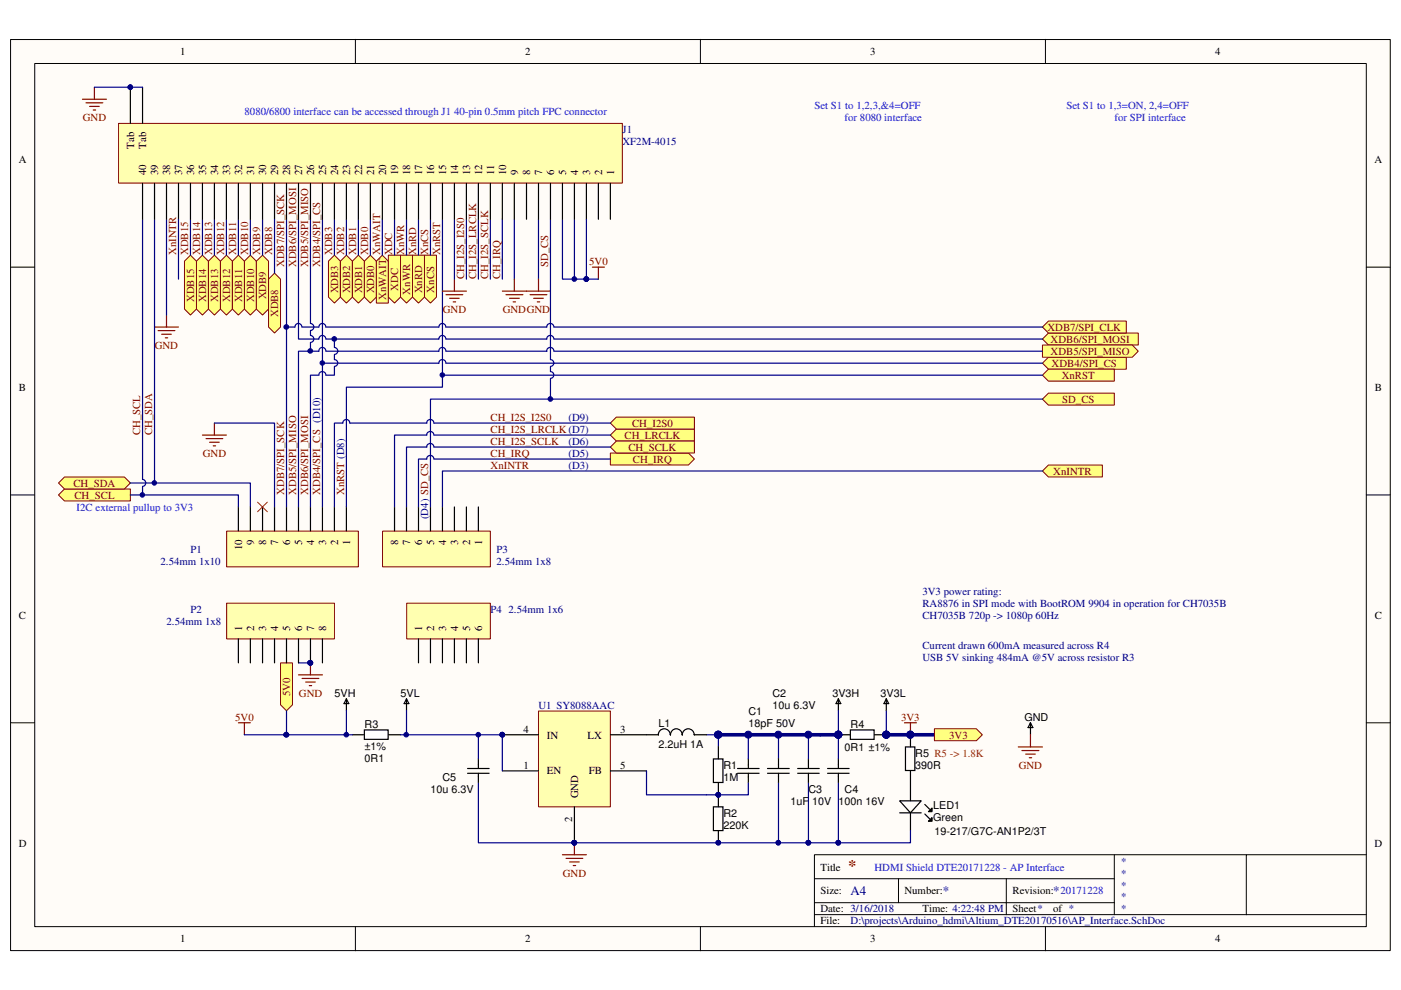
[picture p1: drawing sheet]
<svg xmlns="http://www.w3.org/2000/svg" width="297mm" height="210mm" viewBox="0 0 297 210" stroke-linecap="round" stroke-linejoin="round" font-family="sans-serif">
<defs><g id="words">
<text font-size="3.4" fill="#800000" x="179.8" y="184.6">*</text>
<g font-size="2.8" fill="#000080">
<text x="180.3" y="189.8">A4</text>
<text x="199.9" y="189.8">*</text>
<text x="223.3" y="189.8">*</text>
</g>
<g font-size="2.3">
<text x="38.2" y="11.7">1</text>
<text x="111.4" y="11.7">2</text>
<text x="184.5" y="11.7">3</text>
<text x="257.6" y="11.7">4</text>
<text x="4" y="34.5">A</text>
<text x="28.4" y="31.5" transform="rotate(-90 28.4 31.5)">Tab</text>
<text x="31" y="31.5" transform="rotate(-90 31 31.5)">Tab</text>
<text x="291.4" y="34.5">A</text>
<text x="31" y="37.1" transform="rotate(-90 31 37.1)">40</text>
<text x="33.5" y="37.1" transform="rotate(-90 33.5 37.1)">39</text>
<text x="36.1" y="37.1" transform="rotate(-90 36.1 37.1)">38</text>
<text x="38.6" y="37.1" transform="rotate(-90 38.6 37.1)">37</text>
<text x="41.2" y="37.1" transform="rotate(-90 41.2 37.1)">36</text>
<text x="43.7" y="37.1" transform="rotate(-90 43.7 37.1)">35</text>
<text x="46.3" y="37.1" transform="rotate(-90 46.3 37.1)">34</text>
<text x="48.8" y="37.1" transform="rotate(-90 48.8 37.1)">33</text>
<text x="51.3" y="37.1" transform="rotate(-90 51.3 37.1)">32</text>
<text x="53.9" y="37.1" transform="rotate(-90 53.9 37.1)">31</text>
<text x="56.4" y="37.1" transform="rotate(-90 56.4 37.1)">30</text>
<text x="59" y="37.1" transform="rotate(-90 59 37.1)">29</text>
<text x="61.5" y="37.1" transform="rotate(-90 61.5 37.1)">28</text>
<text x="64.1" y="37.1" transform="rotate(-90 64.1 37.1)">27</text>
<text x="66.6" y="37.1" transform="rotate(-90 66.6 37.1)">26</text>
<text x="69.2" y="37.1" transform="rotate(-90 69.2 37.1)">25</text>
<text x="71.7" y="37.1" transform="rotate(-90 71.7 37.1)">24</text>
<text x="74.2" y="37.1" transform="rotate(-90 74.2 37.1)">23</text>
<text x="76.8" y="37.1" transform="rotate(-90 76.8 37.1)">22</text>
<text x="79.3" y="37.1" transform="rotate(-90 79.3 37.1)">21</text>
<text x="81.9" y="37.1" transform="rotate(-90 81.9 37.1)">20</text>
<text x="84.4" y="37.1" transform="rotate(-90 84.4 37.1)">19</text>
<text x="86.9" y="37.1" transform="rotate(-90 86.9 37.1)">18</text>
<text x="89.5" y="37.1" transform="rotate(-90 89.5 37.1)">17</text>
<text x="92.1" y="37.1" transform="rotate(-90 92.1 37.1)">16</text>
<text x="94.6" y="37.1" transform="rotate(-90 94.6 37.1)">15</text>
<text x="97.2" y="37.1" transform="rotate(-90 97.2 37.1)">14</text>
<text x="99.7" y="37.1" transform="rotate(-90 99.7 37.1)">13</text>
<text x="102.2" y="37.1" transform="rotate(-90 102.2 37.1)">12</text>
<text x="104.8" y="37.1" transform="rotate(-90 104.8 37.1)">11</text>
<text x="107.3" y="37.1" transform="rotate(-90 107.3 37.1)">10</text>
<text x="109.9" y="37.1" transform="rotate(-90 109.9 37.1)">9</text>
<text x="112.4" y="37.1" transform="rotate(-90 112.4 37.1)">8</text>
<text x="114.9" y="37.1" transform="rotate(-90 114.9 37.1)">7</text>
<text x="117.5" y="37.1" transform="rotate(-90 117.5 37.1)">6</text>
<text x="120.1" y="37.1" transform="rotate(-90 120.1 37.1)">5</text>
<text x="122.6" y="37.1" transform="rotate(-90 122.6 37.1)">4</text>
<text x="125.1" y="37.1" transform="rotate(-90 125.1 37.1)">3</text>
<text x="127.7" y="37.1" transform="rotate(-90 127.7 37.1)">2</text>
<text x="130.2" y="37.1" transform="rotate(-90 130.2 37.1)">1</text>
<text x="4" y="82.8">B</text>
<text x="291.5" y="82.8">B</text>
<text x="51.3" y="116.7" transform="rotate(-90 51.3 116.7)">10</text>
<text x="53.9" y="115.5" transform="rotate(-90 53.9 115.5)">9</text>
<text x="56.4" y="115.5" transform="rotate(-90 56.4 115.5)">8</text>
<text x="59" y="115.5" transform="rotate(-90 59 115.5)">7</text>
<text x="61.5" y="115.5" transform="rotate(-90 61.5 115.5)">6</text>
<text x="64.1" y="115.5" transform="rotate(-90 64.1 115.5)">5</text>
<text x="66.6" y="115.5" transform="rotate(-90 66.6 115.5)">4</text>
<text x="69.2" y="115.5" transform="rotate(-90 69.2 115.5)">3</text>
<text x="71.7" y="115.5" transform="rotate(-90 71.7 115.5)">2</text>
<text x="74.2" y="115.5" transform="rotate(-90 74.2 115.5)">1</text>
<text x="84.4" y="115.5" transform="rotate(-90 84.4 115.5)">8</text>
<text x="86.9" y="115.5" transform="rotate(-90 86.9 115.5)">7</text>
<text x="89.5" y="115.5" transform="rotate(-90 89.5 115.5)">6</text>
<text x="92.1" y="115.5" transform="rotate(-90 92.1 115.5)">5</text>
<text x="94.6" y="115.5" transform="rotate(-90 94.6 115.5)">4</text>
<text x="97.2" y="115.5" transform="rotate(-90 97.2 115.5)">3</text>
<text x="99.7" y="115.5" transform="rotate(-90 99.7 115.5)">2</text>
<text x="102.2" y="115.5" transform="rotate(-90 102.2 115.5)">1</text>
<text x="4" y="131.2">C</text>
<text x="291.5" y="131.2">C</text>
<text x="51.3" y="133.7" transform="rotate(-90 51.3 133.7)">1</text>
<text x="53.9" y="133.7" transform="rotate(-90 53.9 133.7)">2</text>
<text x="56.4" y="133.7" transform="rotate(-90 56.4 133.7)">3</text>
<text x="59" y="133.7" transform="rotate(-90 59 133.7)">4</text>
<text x="61.5" y="133.7" transform="rotate(-90 61.5 133.7)">5</text>
<text x="64.1" y="133.7" transform="rotate(-90 64.1 133.7)">6</text>
<text x="66.6" y="133.7" transform="rotate(-90 66.6 133.7)">7</text>
<text x="69.2" y="133.7" transform="rotate(-90 69.2 133.7)">8</text>
<text x="89.5" y="133.7" transform="rotate(-90 89.5 133.7)">1</text>
<text x="92.1" y="133.7" transform="rotate(-90 92.1 133.7)">2</text>
<text x="94.6" y="133.7" transform="rotate(-90 94.6 133.7)">3</text>
<text x="97.2" y="133.7" transform="rotate(-90 97.2 133.7)">4</text>
<text x="99.7" y="133.7" transform="rotate(-90 99.7 133.7)">5</text>
<text x="102.2" y="133.7" transform="rotate(-90 102.2 133.7)">6</text>
<text x="70.9" y="147.7">5VH</text>
<text x="84.9" y="147.7">5VL</text>
<text x="163.8" y="147.7">C2</text>
<text x="176.5" y="147.7">3V3H</text>
<text x="186.7" y="147.7">3V3L</text>
<text x="77.3" y="154.3">R3</text>
<text x="111" y="155.3">4</text>
<text x="131.5" y="155.3">3</text>
<text x="139.6" y="154.1">L1</text>
<text x="158.7" y="154.1">18pF 50V</text>
<text x="158.7" y="151.5">C1</text>
<text x="163.8" y="150.2">10u 6.3V</text>
<text x="180.3" y="154.3">R4</text>
<text x="217.2" y="152.8">GND</text>
<text x="77.3" y="158.9">±1%</text>
<text x="77.3" y="161.5">0R1</text>
<text x="115.9" y="156.6">IN</text>
<text x="124.6" y="156.6">LX</text>
<text x="139.6" y="158.7">2.2uH 1A</text>
<text x="179.1" y="159.2">0R1 ±1%</text>
<text x="194.1" y="160.4">R5 R5 -&gt; 1.8K</text>
<text x="93.8" y="165.5">C5</text>
<text x="111" y="162.9">1</text>
<text x="115.9" y="164.2">EN</text>
<text x="124.8" y="164.2">FB</text>
<text x="131.5" y="162.9">5</text>
<text x="153.4" y="165.5">1M</text>
<text x="153.4" y="163">R1</text>
<text x="194.1" y="163">390R</text>
<text x="91.3" y="168.1">10u 6.3V</text>
<text x="122.6" y="169.3" transform="rotate(-90 122.6 169.3)">GND</text>
<text x="153.4" y="173.1">R2</text>
<text x="167.6" y="170.6">1uF 10V</text>
<text x="171.4" y="168.1">C3</text>
<text x="177.8" y="170.6">100n 16V</text>
<text x="179.1" y="168.1">C4</text>
<text x="197.9" y="171.6">LED1</text>
<text x="4" y="179.5">D</text>
<text x="121.3" y="174.2" transform="rotate(-90 121.3 174.2)">2</text>
<text x="153.4" y="175.7">220K</text>
<text x="197.9" y="174.2">Green</text>
<text x="198.1" y="177">19-217/G7C-AN1P2/3T</text>
<text x="291.4" y="179.5">D</text>
<text x="173.9" y="184.6">Title</text>
<text x="173.9" y="189.7">Size:</text>
<text x="191.8" y="189.7">Number:</text>
<text x="214.7" y="189.7">Revision: 20171228</text>
<text x="173.9" y="193.5">Date: 3/16/2018</text>
<text x="173.9" y="196">File:</text>
<text x="195.6" y="193.5">Time: 4:22:48 PM</text>
<text x="214.7" y="193.5">Sheet*</text>
<text x="223.3" y="193.5">of *</text>
<text x="38.2" y="199.8">1</text>
<text x="111.4" y="199.8">2</text>
<text x="184.5" y="199.8">3</text>
<text x="257.6" y="199.8">4</text>
</g>
<g font-size="2.3" fill="#00f">
<text x="172.7" y="23.1">Set S1 to 1,2,3,&amp;4=OFF</text>
<text x="226.1" y="23.1">Set S1 to 1,3=ON, 2,4=OFF</text>
<text x="51.9" y="24.4">8080/6800 interface can be accessed through J1 40-pin 0.5mm pitch FPC connector</text>
<text x="179.1" y="25.7">for 8080 interface</text>
<text x="236.3" y="25.7">for SPI interface</text>
<text x="16.3" y="108.3">I2C external pullup to 3V3</text>
<text x="185.4" y="184.6">HDMI Shield DTE20171228 - AP Interface</text>
</g>
<g font-size="2.3" fill="#800000">
<text x="17.6" y="25.7">GND</text>
<text x="37.4" y="54.1" transform="rotate(-90 37.4 54.1)">XnINTR</text>
<text x="39.9" y="54.1" transform="rotate(-90 39.9 54.1)">XDB15</text>
<text x="42.5" y="54.1" transform="rotate(-90 42.5 54.1)">XDB14</text>
<text x="45" y="54.1" transform="rotate(-90 45 54.1)">XDB13</text>
<text x="47.5" y="54.1" transform="rotate(-90 47.5 54.1)">XDB12</text>
<text x="50.1" y="54.1" transform="rotate(-90 50.1 54.1)">XDB11</text>
<text x="52.6" y="54.1" transform="rotate(-90 52.6 54.1)">XDB10</text>
<text x="55.2" y="54.1" transform="rotate(-90 55.2 54.1)">XDB9</text>
<text x="57.7" y="54.1" transform="rotate(-90 57.7 54.1)">XDB8</text>
<text x="60.2" y="56.7" transform="rotate(-90 60.2 56.7)">XDB7/SPI_SCK</text>
<text x="62.8" y="56.7" transform="rotate(-90 62.8 56.7)">XDB6/SPI_MOSI</text>
<text x="65.4" y="56.7" transform="rotate(-90 65.4 56.7)">XDB5/SPI_MISO</text>
<text x="67.9" y="56.7" transform="rotate(-90 67.9 56.7)">XDB4/SPI_CS</text>
<text x="70.4" y="54.1" transform="rotate(-90 70.4 54.1)">XDB3</text>
<text x="73" y="54.1" transform="rotate(-90 73 54.1)">XDB2</text>
<text x="75.5" y="54.1" transform="rotate(-90 75.5 54.1)">XDB1</text>
<text x="78.1" y="54.1" transform="rotate(-90 78.1 54.1)">XDB0</text>
<text x="80.6" y="54.1" transform="rotate(-90 80.6 54.1)">XnWAIT</text>
<text x="83.1" y="54.1" transform="rotate(-90 83.1 54.1)">XDC</text>
<text x="85.7" y="54.1" transform="rotate(-90 85.7 54.1)">XnWR</text>
<text x="88.2" y="54.1" transform="rotate(-90 88.2 54.1)">XnRD</text>
<text x="90.8" y="54.1" transform="rotate(-90 90.8 54.1)">XnCS</text>
<text x="93.3" y="54.1" transform="rotate(-90 93.3 54.1)">XnRST</text>
<text x="98.4" y="59.2" transform="rotate(-90 98.4 59.2)">CH_I2S_I2S0</text>
<text x="101" y="59.2" transform="rotate(-90 101 59.2)">CH_I2S_LRCLK</text>
<text x="103.5" y="59.2" transform="rotate(-90 103.5 59.2)">CH_I2S_SCLK</text>
<text x="106" y="59.2" transform="rotate(-90 106 59.2)">CH_IRQ</text>
<text x="116.2" y="56.7" transform="rotate(-90 116.2 56.7)">SD_CS</text>
<text x="124.9" y="56.2">5V0</text>
<text x="41.2" y="64.1" transform="rotate(-90 41.2 64.1)">XDB15</text>
<text x="43.7" y="64.1" transform="rotate(-90 43.7 64.1)">XDB14</text>
<text x="46.3" y="64.1" transform="rotate(-90 46.3 64.1)">XDB13</text>
<text x="48.8" y="64.1" transform="rotate(-90 48.8 64.1)">XDB12</text>
<text x="51.3" y="64.1" transform="rotate(-90 51.3 64.1)">XDB11</text>
<text x="53.9" y="64.1" transform="rotate(-90 53.9 64.1)">XDB10</text>
<text x="56.4" y="63.5" transform="rotate(-90 56.4 63.5)">XDB9</text>
<text x="71.7" y="62.2" transform="rotate(-90 71.7 62.2)">XDB3</text>
<text x="74.2" y="62.2" transform="rotate(-90 74.2 62.2)">XDB2</text>
<text x="76.8" y="62.2" transform="rotate(-90 76.8 62.2)">XDB1</text>
<text x="79.3" y="62.2" transform="rotate(-90 79.3 62.2)">XDB0</text>
<text x="81.9" y="63.6" transform="rotate(-90 81.9 63.6)">XnWAIT</text>
<text x="84.4" y="61.6" transform="rotate(-90 84.4 61.6)">XDC</text>
<text x="86.9" y="62.4" transform="rotate(-90 86.9 62.4)">XnWR</text>
<text x="89.5" y="62.2" transform="rotate(-90 89.5 62.2)">XnRD</text>
<text x="92.1" y="62" transform="rotate(-90 92.1 62)">XnCS</text>
<text x="59" y="67.3" transform="rotate(-90 59 67.3)">XDB8</text>
<text x="93.9" y="66.3">GND</text>
<text x="106.6" y="66.3">GNDGND</text>
<text x="222.1" y="70.1">XDB7/SPI_CLK</text>
<text x="32.8" y="74">GND</text>
<text x="222.8" y="72.7">XDB6/SPI_MOSI</text>
<text x="222.8" y="75.2">XDB5/SPI_MISO</text>
<text x="223" y="77.8">XDB4/SPI_CS</text>
<text x="225.1" y="80.3">XnRST</text>
<text x="104" y="89.2">CH_I2S_I2S0</text>
<text x="225.2" y="85.4">SD_CS</text>
<text x="29.7" y="92.2" transform="rotate(-90 29.7 92.2)">CH_SCL</text>
<text x="32.3" y="92.2" transform="rotate(-90 32.3 92.2)">CH_SDA</text>
<text x="104" y="94.3">CH_I2S_SCLK</text>
<text x="104" y="91.8">CH_I2S_LRCLK(D7)</text>
<text x="132.4" y="93">CH_LRCLK</text>
<text x="133.2" y="95.6">CH_SCLK</text>
<text x="134" y="90.5">CH_I2S0</text>
<text x="43" y="96.9">GND</text>
<text x="104" y="96.9">CH_IRQ</text>
<text x="104" y="99.4">XnINTR</text>
<text x="134.2" y="98.1">CH_IRQ</text>
<text x="223.3" y="100.7">XnINTR</text>
<text x="15.6" y="103.2">CH_SDA</text>
<text x="15.8" y="105.7">CH_SCL</text>
<text x="60.2" y="105" transform="rotate(-90 60.2 105)">XDB7/SPI_SCK</text>
<text x="62.8" y="105" transform="rotate(-90 62.8 105)">XDB5/SPI_MISO</text>
<text x="65.4" y="105" transform="rotate(-90 65.4 105)">XDB6/SPI_MOSI</text>
<text x="67.9" y="105" transform="rotate(-90 67.9 105)">XDB4/SPI_CS (D10)</text>
<text x="73" y="105" transform="rotate(-90 73 105)">XnRST (D8)</text>
<text x="61.5" y="147.6" transform="rotate(-90 61.5 147.6)">5V0</text>
<text x="63.4" y="147.7">GND</text>
<text x="49.9" y="152.8">5V0</text>
<text x="191" y="152.8">3V3</text>
<text x="201.2" y="156.6">3V3</text>
<text x="216" y="162.9">GND</text>
<text x="119.3" y="185.8">GND</text>
</g>
<g font-size="2.3" fill="#000080">
<text x="132" y="28.2">J1</text>
<text x="132" y="30.7">XF2M-4015</text>
<text x="120.5" y="89.2">(D9)</text>
<text x="120.5" y="94.3">(D6)</text>
<text x="120.5" y="96.9">(D5)</text>
<text x="120.5" y="99.4">(D3)</text>
<text x="90.8" y="110.1" transform="rotate(-90 90.8 110.1)">(D4) SD_CS</text>
<text x="34" y="119.7">2.54mm 1x10</text>
<text x="40.4" y="117.2">P1</text>
<text x="105.3" y="117.2">P3</text>
<text x="105.3" y="119.7">2.54mm 1x8</text>
<text x="40.4" y="129.9">P2</text>
<text x="104" y="129.9">P4 2.54mm 1x6</text>
<text x="195.6" y="126.1">3V3 power rating:</text>
<text x="195.6" y="128.7">RA8876 in SPI mode with BootROM 9904 in operation for CH7035B</text>
<text x="195.6" y="131.2">CH7035B 720p -&gt; 1080p 60Hz</text>
<text x="35.3" y="132.5">2.54mm 1x8</text>
<text x="195.6" y="137.5">Current drawn 600mA measured across R4</text>
<text x="195.6" y="140.1">USB 5V sinking 484mA @5V across resistor R3</text>
<text x="114.2" y="150.2">U1 SY8088AAC</text>
<text x="237.6" y="183.3">*</text>
<text x="237.6" y="185.8">*</text>
<text x="237.6" y="188.4">*</text>
<text x="237.6" y="190.9">*</text>
<text x="180.3" y="196">D:\projects\Arduino_hdmi\Altium_DTE20170516\AP_Interface.SchDoc</text>
<text x="237.6" y="193.5">*</text>
</g>
</g></defs>
<path d="M2.3 8.4h292.5v193.1h-292.5z" fill="#fffcf8"/>
<path d="M2.2 8.4h292.6v193.1h-292.6z" fill="none" stroke="#000" stroke-width=".21"/>
<path d="M7.4 13.5h282.3v183h-282.3z" fill="#fffcf8"/>
<g fill="none" stroke="#000" stroke-width=".21">
<path d="M7.4 13.5h282.3v183h-282.3zM75.3 8.3v5.1M148.5 8.3v5.1M221.7 8.3v5.1M2.2 56.6h5.1M289.7 56.6h5.1M2.2 104.9h5.1M289.7 104.9h5.1M2.2 153.2h5.1M289.7 153.2h5.1M75.3 196.5v5.1M148.5 196.5v5.1"/>
<path d="M172.7 186.3h63.6M172.7 193.9h117M172.7 191.4h63.6M190.5 186.3v5.1M213.4 186.3v7.6M221.7 196.5v5.1M236.3 181.2v12.7M264.2 181.2h-91.5v15.3M289.7 181.2h-25.5v12.7"/>
</g>
<path d="M63.3 143.1h5.1M64 143.8h3.6M64.8 144.6h2M65.6 145.4h.5M65.8 140.5v2.6" fill="none" stroke="#800000" stroke-width=".25"/>
<circle cx="65.8" cy="140.5" r=".49" fill="#000080"/>
<circle cx="65.8" cy="140.5" r=".49" fill="none" stroke="#000080" stroke-width=".21"/>
<path d="M42.9 92.2h5.1M43.7 93h3.5M44.4 93.8h2.1M45.2 94.5h.5M45.5 89.7v2.5M50.5 153.2h2.6M51.8 153.2v2.6" fill="none" stroke="#800000" stroke-width=".25"/>
<path d="M59.5 140.5h2.5v8.9l-1.3 1.3-1.2-1.3z" fill-rule="evenodd" fill="#ffff80"/>
<path d="M59.5 140.5h2.5v8.9l-1.3 1.3-1.2-1.3z" fill="none" stroke="#800000" stroke-width=".21"/>
<path d="M12.4 104.9l1.3-1.2h13.9v2.5h-13.9z" fill-rule="evenodd" fill="#ffff80"/>
<path d="M12.4 104.9l1.3-1.2h13.9v2.5h-13.9z" fill="none" stroke="#800000" stroke-width=".21"/>
<path d="M12.4 102.4l1.3-1.3h12.7l1.2 1.3-1.2 1.3h-12.7z" fill-rule="evenodd" fill="#ffff80"/>
<path d="M12.4 102.4l1.3-1.3h12.7l1.2 1.3-1.2 1.3h-12.7z" fill="none" stroke="#800000" stroke-width=".21"/>
<path d="M221 77l1.3-1.3h16.5v2.6h-16.5z" fill-rule="evenodd" fill="#ffff80"/>
<path d="M221 77l1.3-1.3h16.5v2.6h-16.5z" fill="none" stroke="#800000" stroke-width=".21"/>
<path d="M221 71.9l1.3-1.3h19v2.6h-19z" fill-rule="evenodd" fill="#ffff80"/>
<path d="M221 71.9l1.3-1.3h19v2.6h-19z" fill="none" stroke="#800000" stroke-width=".21"/>
<path d="M221 69.3l1.3-1.2h16.5v2.5h-16.5z" fill-rule="evenodd" fill="#ffff80"/>
<path d="M221 69.3l1.3-1.2h16.5v2.5h-16.5z" fill="none" stroke="#800000" stroke-width=".21"/>
<path d="M221 79.5l1.3-1.2h14v2.5h-14z" fill-rule="evenodd" fill="#ffff80"/>
<path d="M221 79.5l1.3-1.2h14v2.5h-14z" fill="none" stroke="#800000" stroke-width=".21"/>
<path d="M129.4 96.1h16.6l1.2 1.2-1.2 1.3h-16.6z" fill-rule="evenodd" fill="#ffff80"/>
<path d="M129.4 96.1h16.6l1.2 1.2-1.2 1.3h-16.6z" fill="none" stroke="#800000" stroke-width=".21"/>
<path d="M221 73.2h19.1l1.2 1.3-1.2 1.2h-19.1z" fill-rule="evenodd" fill="#ffff80"/>
<path d="M221 73.2h19.1l1.2 1.3-1.2 1.2h-19.1z" fill="none" stroke="#800000" stroke-width=".21"/>
<path d="M221 84.6l1.3-1.2h14v2.5h-14z" fill-rule="evenodd" fill="#ffff80"/>
<path d="M221 84.6l1.3-1.2h14v2.5h-14z" fill="none" stroke="#800000" stroke-width=".21"/>
<path d="M42.9 54.1l1.3 1.3v10.1l-1.3 1.3-1.2-1.3v-10.1z" fill-rule="evenodd" fill="#ffff80"/>
<path d="M42.9 54.1l1.3 1.3v10.1l-1.3 1.3-1.2-1.3v-10.1z" fill="none" stroke="#800000" stroke-width=".21"/>
<path d="M46.7 55.4l1.3-1.3 1.3 1.3v10.1l-1.3 1.3-1.3-1.3z" fill-rule="evenodd" fill="#ffff80"/>
<path d="M46.7 55.4l1.3-1.3 1.3 1.3v10.1l-1.3 1.3-1.3-1.3z" fill="none" stroke="#800000" stroke-width=".21"/>
<path d="M51.8 55.4l1.3-1.3 1.3 1.3v10.1l-1.3 1.3-1.3-1.3z" fill-rule="evenodd" fill="#ffff80"/>
<path d="M51.8 55.4l1.3-1.3 1.3 1.3v10.1l-1.3 1.3-1.3-1.3z" fill="none" stroke="#800000" stroke-width=".21"/>
<path d="M56.9 59.2l1.3-1.3 1.3 1.3v10.1l-1.3 1.3-1.3-1.3z" fill-rule="evenodd" fill="#ffff80"/>
<path d="M56.9 59.2l1.3-1.3 1.3 1.3v10.1l-1.3 1.3-1.3-1.3z" fill="none" stroke="#800000" stroke-width=".21"/>
<path d="M221 99.9l1.3-1.3h11.4v2.5h-11.4z" fill-rule="evenodd" fill="#ffff80"/>
<path d="M221 99.9l1.3-1.3h11.4v2.5h-11.4z" fill="none" stroke="#800000" stroke-width=".21"/>
<path d="M39.1 55.4l1.3-1.3 1.3 1.3v10.1l-1.3 1.3-1.3-1.3z" fill-rule="evenodd" fill="#ffff80"/>
<path d="M39.1 55.4l1.3-1.3 1.3 1.3v10.1l-1.3 1.3-1.3-1.3z" fill="none" stroke="#800000" stroke-width=".21"/>
<path d="M44.2 55.4l1.3-1.3 1.2 1.3v10.1l-1.2 1.3-1.3-1.3z" fill-rule="evenodd" fill="#ffff80"/>
<path d="M44.2 55.4l1.3-1.3 1.2 1.3v10.1l-1.2 1.3-1.3-1.3z" fill="none" stroke="#800000" stroke-width=".21"/>
<path d="M49.3 55.4l1.2-1.3 1.3 1.3v10.1l-1.3 1.3-1.2-1.3z" fill-rule="evenodd" fill="#ffff80"/>
<path d="M49.3 55.4l1.2-1.3 1.3 1.3v10.1l-1.3 1.3-1.2-1.3z" fill="none" stroke="#800000" stroke-width=".21"/>
<path d="M54.4 55.4l1.3-1.3 1.2 1.3v10.1l-1.2 1.3-1.3-1.3z" fill-rule="evenodd" fill="#ffff80"/>
<path d="M54.4 55.4l1.3-1.3 1.2 1.3v10.1l-1.2 1.3-1.3-1.3z" fill="none" stroke="#800000" stroke-width=".21"/>
<path d="M69.6 55.4l1.3-1.3 1.3 1.3v7.6l-1.3 1.3-1.3-1.3z" fill-rule="evenodd" fill="#ffff80"/>
<path d="M69.6 55.4l1.3-1.3 1.3 1.3v7.6l-1.3 1.3-1.3-1.3z" fill="none" stroke="#800000" stroke-width=".21"/>
<path d="M72.2 55.4l1.2-1.3 1.3 1.3v7.6l-1.3 1.3-1.2-1.3z" fill-rule="evenodd" fill="#ffff80"/>
<path d="M72.2 55.4l1.2-1.3 1.3 1.3v7.6l-1.3 1.3-1.2-1.3z" fill="none" stroke="#800000" stroke-width=".21"/>
<path d="M74.7 55.4l1.3-1.3 1.3 1.3v7.6l-1.3 1.3-1.3-1.3z" fill-rule="evenodd" fill="#ffff80"/>
<path d="M74.7 55.4l1.3-1.3 1.3 1.3v7.6l-1.3 1.3-1.3-1.3z" fill="none" stroke="#800000" stroke-width=".21"/>
<path d="M77.3 55.4l1.2-1.3 1.3 1.3v7.6l-1.3 1.3-1.2-1.3z" fill-rule="evenodd" fill="#ffff80"/>
<path d="M77.3 55.4l1.2-1.3 1.3 1.3v7.6l-1.3 1.3-1.2-1.3z" fill="none" stroke="#800000" stroke-width=".21"/>
<path d="M79.8 55.4l1.3-1.3 1.2 1.3v8.9h-2.5z" fill-rule="evenodd" fill="#ffff80"/>
<path d="M79.8 55.4l1.3-1.3 1.2 1.3v8.9h-2.5z" fill="none" stroke="#800000" stroke-width=".21"/>
<path d="M82.3 54.1h2.6v8.9l-1.3 1.3-1.3-1.3z" fill-rule="evenodd" fill="#ffff80"/>
<path d="M82.3 54.1h2.6v8.9l-1.3 1.3-1.3-1.3z" fill="none" stroke="#800000" stroke-width=".21"/>
<path d="M84.9 54.1h2.6v8.9l-1.3 1.3-1.3-1.3z" fill-rule="evenodd" fill="#ffff80"/>
<path d="M84.9 54.1h2.6v8.9l-1.3 1.3-1.3-1.3z" fill="none" stroke="#800000" stroke-width=".21"/>
<path d="M90 54.1h2.5v8.9l-1.2 1.3-1.3-1.3z" fill-rule="evenodd" fill="#ffff80"/>
<path d="M90 54.1h2.5v8.9l-1.2 1.3-1.3-1.3z" fill="none" stroke="#800000" stroke-width=".21"/>
<path d="M87.5 54.1h2.5v8.9l-1.3 1.3-1.2-1.3z" fill-rule="evenodd" fill="#ffff80"/>
<path d="M87.5 54.1h2.5v8.9l-1.3 1.3-1.2-1.3z" fill="none" stroke="#800000" stroke-width=".21"/>
<path d="M125.6 56.6h2.5M126.9 56.6v2.6" fill="none" stroke="#800000" stroke-width=".25"/>
<path d="M63.3 140.5h2.5" fill="none" stroke="#000080" stroke-width=".25"/>
<circle cx="65.8" cy="140.5" r=".49" fill="#000080"/>
<circle cx="65.8" cy="140.5" r=".49" fill="none" stroke="#000080" stroke-width=".21"/>
<path d="M129.4 92.2l1.3-1.2h16.5v2.5h-16.5z" fill-rule="evenodd" fill="#ffff80"/>
<path d="M129.4 92.2l1.3-1.2h16.5v2.5h-16.5z" fill="none" stroke="#800000" stroke-width=".21"/>
<path d="M129.4 94.8l1.3-1.3h16.5v2.6h-16.5z" fill-rule="evenodd" fill="#ffff80"/>
<path d="M129.4 94.8l1.3-1.3h16.5v2.6h-16.5z" fill="none" stroke="#800000" stroke-width=".21"/>
<path d="M129.4 89.7l1.3-1.3h16.5v2.6h-16.5z" fill-rule="evenodd" fill="#ffff80"/>
<path d="M129.4 89.7l1.3-1.3h16.5v2.6h-16.5z" fill="none" stroke="#800000" stroke-width=".21"/>
<path d="M48.1 112.6h27.9v7.6h-27.9z" fill="#ffffb0"/>
<path d="M48 112.6h28v7.6h-28z" fill="none" stroke="#800000" stroke-width=".21"/>
<path d="M50.5 107.5v5.1M53.1 107.5v5.1M55.7 107.5v5.1M58.2 107.5v5.1M60.7 107.5v5.1M63.3 107.5v5.1M65.8 107.5v5.1M68.4 107.5v5.1M70.9 107.5v5.1M73.4 107.5v5.1" fill="none" stroke="#000" stroke-width=".25"/>
<path d="M81.1 112.6h22.9v7.6h-22.9z" fill="#ffffb0"/>
<path d="M81.1 112.6h22.9v7.6h-22.9z" fill="none" stroke="#800000" stroke-width=".21"/>
<path d="M83.6 107.5v5.1M86.2 107.5v5.1M88.7 107.5v5.1M91.3 107.5v5.1M93.8 107.5v5.1M96.3 107.5v5.1M98.9 107.5v5.1M101.4 107.5v5.1" fill="none" stroke="#000" stroke-width=".25"/>
<path d="M48.1 127.9h22.8v7.6h-22.8z" fill="#ffffb0"/>
<path d="M48 127.9h22.9v7.6h-22.9z" fill="none" stroke="#800000" stroke-width=".21"/>
<path d="M50.5 135.5v5M53.1 135.5v5M55.7 135.5v5M58.2 135.5v5M60.7 135.5v5M63.3 135.5v5M65.8 135.5v5" fill="none" stroke="#000" stroke-width=".25"/>
<circle cx="65.8" cy="140.5" r=".49" fill="#000080"/>
<circle cx="65.8" cy="140.5" r=".49" fill="none" stroke="#000080" stroke-width=".21"/>
<path d="M68.4 135.5v5" fill="none" stroke="#000" stroke-width=".25"/>
<circle cx="65.8" cy="140.5" r=".49" fill="#000080"/>
<circle cx="65.8" cy="140.5" r=".49" fill="none" stroke="#000080" stroke-width=".21"/>
<path d="M86.3 127.9h17.7v7.6h-17.7z" fill="#ffffb0"/>
<path d="M86.2 127.9h17.8v7.6h-17.8z" fill="none" stroke="#800000" stroke-width=".21"/>
<path d="M88.7 135.5v5M91.3 135.5v5M93.8 135.5v5M96.3 135.5v5M98.9 135.5v5M101.4 135.5v5" fill="none" stroke="#000" stroke-width=".25"/>
<g fill="none" stroke="#000080" stroke-width=".25">
<path d="M40.4 46.5v7.6M42.9 46.5v7.6M45.5 46.5v7.6M48 46.5v7.6M50.5 46.5v7.6M53.1 46.5v7.6M55.7 46.5v7.6M60.7 46.5v61M68.4 46.5v61M70.9 46.5v7.6M73.4 46.5v7.6M76 46.5v7.6"/>
<path d="M78.5 46.5v7.6M81.1 46.5v7.6M83.6 46.5v7.6M86.2 46.5v7.6M88.7 46.5v7.6M91.3 46.5v7.6M93.8 46.5v35.6h-20.4v25.4M68.4 77h24.6a.74 .74 0 0 1 .8-.8 .74 .74 0 0 1 .7 .8M94.6 77h126.4M45.5 89.7h12.7v17.8"/>
</g>
<path d="M54.6 106.5l2.1 2M56.7 106.5l-2.1 2" fill="none" stroke="#f00" stroke-width=".21"/>
<circle cx="68.4" cy="77" r=".48" fill="#000080"/>
<circle cx="68.4" cy="77" r=".48" fill="none" stroke="#000080" stroke-width=".21"/>
<path d="M93.8 79.5h127.2" fill="none" stroke="#000080" stroke-width=".25"/>
<circle cx="93.8" cy="79.5" r=".48" fill="#000080"/>
<circle cx="93.8" cy="79.5" r=".48" fill="none" stroke="#000080" stroke-width=".21"/>
<path d="M32.8 69.3h5M33.5 70.1h3.6M34.3 70.9h2M35 71.6h.6M35.3 66.8v2.5" fill="none" stroke="#800000" stroke-width=".25"/>
<path d="M32.8 46.5v55.9M35.3 46.5v20.3M27.6 104.9h22.9v2.6M27.6 102.4h25.5v5.1" fill="none" stroke="#000080" stroke-width=".25"/>
<circle cx="32.7" cy="102.4" r=".48" fill="#000080"/>
<circle cx="32.7" cy="102.4" r=".48" fill="none" stroke="#000080" stroke-width=".21"/>
<path d="M30.2 46.5v55.1a.74 .74 0 0 1 .7 .8 .74 .74 0 0 1-.7 .7v1.8" fill="none" stroke="#000080" stroke-width=".25"/>
<circle cx="30.2" cy="104.9" r=".48" fill="#000080"/>
<circle cx="30.2" cy="104.9" r=".48" fill="none" stroke="#000080" stroke-width=".21"/>
<path d="M104 46.5v12.7M106.5 46.5v12.7M109 46.5v12.7" fill="none" stroke="#000080" stroke-width=".25"/>
<path d="M114.2 150.8h15.2v20.3h-15.2z" fill="#ffffb0"/>
<path d="M114.2 150.7h15.2v20.4h-15.2z" fill="none" stroke="#800000" stroke-width=".21"/>
<path d="M129.4 155.8h7.7M121.8 171.1v7.6" fill="none" stroke="#000" stroke-width=".25"/>
<circle cx="121.8" cy="178.7" r=".49" fill="#000080"/>
<circle cx="121.8" cy="178.7" r=".49" fill="none" stroke="#000080" stroke-width=".21"/>
<path d="M106.5 155.8h7.7" fill="none" stroke="#000" stroke-width=".25"/>
<circle cx="106.5" cy="155.8" r=".48" fill="#000080"/>
<circle cx="106.5" cy="155.8" r=".48" fill="none" stroke="#000080" stroke-width=".21"/>
<path d="M106.5 163.4h7.7M129.4 163.4h7.7" fill="none" stroke="#000" stroke-width=".25"/>
<circle cx="121.8" cy="178.7" r=".49" fill="#000080"/>
<circle cx="121.8" cy="178.7" r=".49" fill="none" stroke="#000080" stroke-width=".21"/>
<circle cx="106.5" cy="155.8" r=".48" fill="#000080"/>
<circle cx="106.5" cy="155.8" r=".48" fill="none" stroke="#000080" stroke-width=".21"/>
<path d="M99.1 164h4.6M99.1 162.9h4.6M101.4 160.9v2M101.4 164v2M169.1 164h4.6M169.1 162.9h4.6M171.4 160.9v2M171.4 164v2M175.5 164h4.5M175.5 162.9h4.5M177.8 160.9v2M177.8 164v2" fill="none" stroke="#000" stroke-width=".25"/>
<path d="M121.8 178.7v2.5M119.2 181.2h5.1M120 182h3.6M120.8 182.8h2M121.5 183.5h.5" fill="none" stroke="#800000" stroke-width=".25"/>
<circle cx="121.8" cy="178.7" r=".49" fill="#000080"/>
<circle cx="121.8" cy="178.7" r=".49" fill="none" stroke="#000080" stroke-width=".21"/>
<path d="M191.8 153.2h2.5M193 153.2v2.6" fill="none" stroke="#800000" stroke-width=".25"/>
<circle cx="193" cy="155.8" r=".73" fill="#000080"/>
<circle cx="193" cy="155.8" r=".73" fill="none" stroke="#000080" stroke-width=".21"/>
<path d="M152.3 176.1v2.6" fill="none" stroke="#000" stroke-width=".25"/>
<circle cx="152.3" cy="178.7" r=".49" fill="#000080"/>
<circle cx="152.3" cy="178.7" r=".49" fill="none" stroke="#000080" stroke-width=".21"/>
<path d="M152.3 168.5v2.6" fill="none" stroke="#000" stroke-width=".25"/>
<circle cx="152.3" cy="168.5" r=".49" fill="#000080"/>
<circle cx="152.3" cy="168.5" r=".49" fill="none" stroke="#000080" stroke-width=".21"/>
<path d="M151.3 171.1h2v5h-2z" fill="none" stroke="#000" stroke-width=".25"/>
<circle cx="152.3" cy="178.7" r=".49" fill="#000080"/>
<circle cx="152.3" cy="178.7" r=".49" fill="none" stroke="#000080" stroke-width=".21"/>
<circle cx="152.3" cy="168.5" r=".49" fill="#000080"/>
<circle cx="152.3" cy="168.5" r=".49" fill="none" stroke="#000080" stroke-width=".21"/>
<path d="M101.4 155.8v5.1" fill="none" stroke="#000080" stroke-width=".25"/>
<circle cx="101.4" cy="155.8" r=".49" fill="#000080"/>
<circle cx="101.4" cy="155.8" r=".49" fill="none" stroke="#000080" stroke-width=".21"/>
<path d="M101.4 166v12.7h20.4M137.1 163.4v5.1h12.7" fill="none" stroke="#000080" stroke-width=".25"/>
<circle cx="121.8" cy="178.7" r=".49" fill="#000080"/>
<circle cx="121.8" cy="178.7" r=".49" fill="none" stroke="#000080" stroke-width=".21"/>
<path d="M156.4 162.9h4.5M156.4 164h4.5M158.7 160.9v2M158.7 164v2" fill="none" stroke="#000" stroke-width=".25"/>
<path d="M158.7 155.8v5.1" fill="none" stroke="#000080" stroke-width=".25"/>
<circle cx="158.6" cy="155.8" r=".74" fill="#000080"/>
<circle cx="158.6" cy="155.8" r=".74" fill="none" stroke="#000080" stroke-width=".21"/>
<path d="M171.4 155.8v5.1" fill="none" stroke="#000080" stroke-width=".25"/>
<circle cx="171.4" cy="155.8" r=".74" fill="#000080"/>
<circle cx="171.4" cy="155.8" r=".74" fill="none" stroke="#000080" stroke-width=".21"/>
<path d="M165.1 155.8v5.1" fill="none" stroke="#000080" stroke-width=".25"/>
<circle cx="165" cy="155.8" r=".73" fill="#000080"/>
<circle cx="165" cy="155.8" r=".73" fill="none" stroke="#000080" stroke-width=".21"/>
<path d="M152.3 155.8h21.6" fill="none" stroke="#000080" stroke-width=".76"/>
<circle cx="152.3" cy="155.8" r=".75" fill="#000080"/>
<circle cx="152.3" cy="155.8" r=".75" fill="none" stroke="#000080" stroke-width=".21"/>
<path d="M177.8 155.8v5.1" fill="none" stroke="#000080" stroke-width=".25"/>
<circle cx="177.7" cy="155.8" r=".74" fill="#000080"/>
<circle cx="177.7" cy="155.8" r=".74" fill="none" stroke="#000080" stroke-width=".21"/>
<path d="M96.3 59.2v2.5M109 59.2v2.5M93.8 61.7h5.1M94.6 62.5h3.5M95.3 63.2h2.1M96.1 64h.5M106.5 61.7h5.1M107.3 62.5h3.6M108 63.2h2.1M108.8 64h.5" fill="none" stroke="#800000" stroke-width=".25"/>
<path d="M96.3 46.5v12.7M114.2 46.5v12.7M121.8 46.5v12.7" fill="none" stroke="#000080" stroke-width=".25"/>
<circle cx="121.8" cy="59.2" r=".49" fill="#000080"/>
<circle cx="121.8" cy="59.2" r=".49" fill="none" stroke="#000080" stroke-width=".21"/>
<path d="M98.9 46.5v12.7M106.5 155.8v7.6" fill="none" stroke="#000080" stroke-width=".25"/>
<path d="M218.5 153.2v2.6M218.5 153.2l.5 1.1h-1z" fill="none" stroke="#000" stroke-width=".25"/>
<circle cx="106.5" cy="155.8" r=".48" fill="#000080"/>
<circle cx="106.5" cy="155.8" r=".48" fill="none" stroke="#000080" stroke-width=".21"/>
<path d="M114.2 59.2v2.5M111.6 61.7h5.1M112.4 62.5h3.5M113.2 63.2h2M113.9 64h.5M215.9 158.4h5.1M216.7 159.1h3.6M217.5 159.9h2M218.5 155.8v2.6M218.2 160.7h.5" fill="none" stroke="#800000" stroke-width=".25"/>
<path d="M101.4 46.5v12.7M116.7 46.5v29.7a.72 .72 0 0 1 .7 .8 .72 .72 0 0 1-.7 .7M116.7 77.8v1a.72 .72 0 0 1 .7 .7 .72 .72 0 0 1-.7 .7M116.7 80.3v4.3M221 84.6h-129.7v22.9" fill="none" stroke="#000080" stroke-width=".25"/>
<circle cx="116.7" cy="84.6" r=".49" fill="#000080"/>
<circle cx="116.7" cy="84.6" r=".49" fill="none" stroke="#000080" stroke-width=".21"/>
<path d="M162.7 164h4.6M162.7 162.9h4.6M165.1 160.9v2M165.1 164v2" fill="none" stroke="#000" stroke-width=".25"/>
<path d="M165.1 166v12.7h6.3" fill="none" stroke="#000080" stroke-width=".25"/>
<circle cx="165" cy="178.7" r=".48" fill="#000080"/>
<circle cx="165" cy="178.7" r=".48" fill="none" stroke="#000080" stroke-width=".21"/>
<circle cx="171.4" cy="178.7" r=".49" fill="#000080"/>
<circle cx="171.4" cy="178.7" r=".49" fill="none" stroke="#000080" stroke-width=".21"/>
<path d="M74.7 155.8h2.6M82.3 155.8h2.6" fill="none" stroke="#000" stroke-width=".25"/>
<path d="M77.3 154.8h5v2h-5z" fill-rule="evenodd" fill="#fff"/>
<path d="M77.3 154.8h5v2h-5zM185.4 155.8h2.5" fill="none" stroke="#000" stroke-width=".25"/>
<circle cx="187.9" cy="155.8" r=".74" fill="#000080"/>
<circle cx="187.9" cy="155.8" r=".74" fill="none" stroke="#000080" stroke-width=".21"/>
<path d="M177.8 155.8h2.5" fill="none" stroke="#000" stroke-width=".25"/>
<circle cx="177.7" cy="155.8" r=".74" fill="#000080"/>
<circle cx="177.7" cy="155.8" r=".74" fill="none" stroke="#000080" stroke-width=".21"/>
<path d="M180.3 154.8h5v2h-5z" fill-rule="evenodd" fill="#fff"/>
<path d="M180.3 154.8h5v2h-5z" fill="none" stroke="#000" stroke-width=".25"/>
<circle cx="187.9" cy="155.8" r=".74" fill="#000080"/>
<circle cx="187.9" cy="155.8" r=".74" fill="none" stroke="#000080" stroke-width=".21"/>
<circle cx="177.7" cy="155.8" r=".74" fill="#000080"/>
<circle cx="177.7" cy="155.8" r=".74" fill="none" stroke="#000080" stroke-width=".21"/>
<path d="M84.9 155.8h21.6" fill="none" stroke="#000080" stroke-width=".25"/>
<circle cx="106.5" cy="155.8" r=".48" fill="#000080"/>
<circle cx="106.5" cy="155.8" r=".48" fill="none" stroke="#000080" stroke-width=".21"/>
<path d="M173.9 155.8h3.9" fill="none" stroke="#000080" stroke-width=".76"/>
<circle cx="177.7" cy="155.8" r=".74" fill="#000080"/>
<circle cx="177.7" cy="155.8" r=".74" fill="none" stroke="#000080" stroke-width=".21"/>
<path d="M73.4 148.2v2.5M73.4 148.2l.6 1h-1.1zM86.2 148.2l.5 1h-1zM86.2 148.2v2.5M177.8 148.2l.5 1h-1.1zM177.8 148.2v2.5M187.9 148.2l.5 1h-1zM187.9 148.2v2.5" fill="none" stroke="#000" stroke-width=".25"/>
<path d="M187.9 155.8h10.2" fill="none" stroke="#000080" stroke-width=".76"/>
<circle cx="187.9" cy="155.8" r=".74" fill="#000080"/>
<circle cx="187.9" cy="155.8" r=".74" fill="none" stroke="#000080" stroke-width=".21"/>
<path d="M63.3 46.5v25.4h4.3a.74 .74 0 0 1 .7-.8 .74 .74 0 0 1 .8 .8M60.7 69.3h1.8a.74 .74 0 0 1 .8-.7 .74 .74 0 0 1 .7 .7h3.6a.74 .74 0 0 1 .7-.7 .74 .74 0 0 1 .8 .7M69.1 74.4a.74 .74 0 0 0-.8-.7 .74 .74 0 0 0-.7 .8h-4.3v33M69.1 71.9h23.9a.74 .74 0 0 1 .8-.8 .74 .74 0 0 1 .7 .8M69.1 69.3h23.9a.74 .74 0 0 1 .8-.7 .74 .74 0 0 1 .7 .7M94.5 74.4a.74 .74 0 0 0-.7-.7 .74 .74 0 0 0-.8 .8h-23.9M94.6 71.9h21.3a.76 .76 0 0 1 .8-.8 .76 .76 0 0 1 .7 .8M94.6 69.3h21.3a.76 .76 0 0 1 .8-.7 .76 .76 0 0 1 .7 .7M117.4 74.4a.76 .76 0 0 0-.8-.7 .76 .76 0 0 0-.7 .8h-21.3M117.5 74.5h103.5M117.5 71.9h103.5M117.5 69.3h103.5" fill="none" stroke="#000080" stroke-width=".25"/>
<circle cx="60.7" cy="69.3" r=".5" fill="#000080"/>
<circle cx="60.7" cy="69.3" r=".5" fill="none" stroke="#000080" stroke-width=".21"/>
<path d="M74.2 89.7a.74 .74 0 0 0-.8-.8 .74 .74 0 0 0-.7 .8h-1.8v17.8M74.2 89.7h16.3a.76 .76 0 0 1 .7-.8 .76 .76 0 0 1 .8 .8M92 92.2a.74 .74 0 0 0-.8-.7 .74 .74 0 0 0-.7 .7h-6.9v15.3M92 94.8a.74 .74 0 0 0-.8-.8 .74 .74 0 0 0-.7 .8h-4.3v12.7M92 97.3a.74 .74 0 0 0-.8-.7 .74 .74 0 0 0-.7 .7h-1.8v10.2M92 89.7h37.4M92 92.2h37.4M92 94.8h37.4M92 97.3h37.4M171.4 166v12.7" fill="none" stroke="#000080" stroke-width=".25"/>
<circle cx="171.4" cy="178.7" r=".49" fill="#000080"/>
<circle cx="171.4" cy="178.7" r=".49" fill="none" stroke="#000080" stroke-width=".21"/>
<path d="M121.8 178.7h43.3M158.7 166v2.5h-8.9" fill="none" stroke="#000080" stroke-width=".25"/>
<circle cx="121.8" cy="178.7" r=".49" fill="#000080"/>
<circle cx="121.8" cy="178.7" r=".49" fill="none" stroke="#000080" stroke-width=".21"/>
<circle cx="165" cy="178.7" r=".48" fill="#000080"/>
<circle cx="165" cy="178.7" r=".48" fill="none" stroke="#000080" stroke-width=".21"/>
<path d="M152.3 155.8v2.6" fill="none" stroke="#000080" stroke-width=".25"/>
<circle cx="152.3" cy="155.8" r=".75" fill="#000080"/>
<circle cx="152.3" cy="155.8" r=".75" fill="none" stroke="#000080" stroke-width=".21"/>
<path d="M149.8 155.8h2.5" fill="none" stroke="#000080" stroke-width=".25"/>
<circle cx="152.3" cy="155.8" r=".75" fill="#000080"/>
<circle cx="152.3" cy="155.8" r=".75" fill="none" stroke="#000080" stroke-width=".21"/>
<path d="M137.1 155.8h2.5M139.6 155.8a1.27 1.27 0 0 1 1.2-1.3 1.27 1.27 0 0 1 1.3 1.3M142.2 155.8a1.25 1.25 0 0 1 1.2-1.3 1.25 1.25 0 0 1 1.2 1.3 1.27 1.27 0 0 1 1.3-1.3 1.27 1.27 0 0 1 1.3 1.3M147.2 155.8h2.6" fill="none" stroke="#000" stroke-width=".25"/>
<path d="M198.1 154.5h8.9l1.3 1.3-1.3 1.3h-8.9z" fill-rule="evenodd" fill="#ffff80"/>
<path d="M198.1 154.5h8.9l1.3 1.3-1.3 1.3h-8.9z" fill="none" stroke="#800000" stroke-width=".21"/>
<path d="M60.7 155.8h14" fill="none" stroke="#000080" stroke-width=".25"/>
<circle cx="60.7" cy="155.8" r=".5" fill="#000080"/>
<circle cx="60.7" cy="155.8" r=".5" fill="none" stroke="#000080" stroke-width=".21"/>
<path d="M60.7 150.7v5.1" fill="none" stroke="#000080" stroke-width=".25"/>
<circle cx="60.7" cy="155.8" r=".5" fill="#000080"/>
<circle cx="60.7" cy="155.8" r=".5" fill="none" stroke="#000080" stroke-width=".21"/>
<path d="M190.8 169.8h4.5l-2.3 2.5zM190.8 172.3h4.5M193 166v3.8M193 172.3v3.8M196.1 172.6l1 1M196.1 170.6l1 1M197.6 173.4v.7h-.8zM197.6 171.3v.8h-.8z" fill="none" stroke="#000" stroke-width=".25"/>
<path d="M197.6 173.4v.7h-.8zM197.6 171.3v.8h-.8z" fill="#000"/>
<path d="M177.8 166v12.7" fill="none" stroke="#000080" stroke-width=".25"/>
<circle cx="177.7" cy="178.7" r=".49" fill="#000080"/>
<circle cx="177.7" cy="178.7" r=".49" fill="none" stroke="#000080" stroke-width=".21"/>
<path d="M171.4 178.7h6.4" fill="none" stroke="#000080" stroke-width=".25"/>
<circle cx="177.7" cy="178.7" r=".49" fill="#000080"/>
<circle cx="177.7" cy="178.7" r=".49" fill="none" stroke="#000080" stroke-width=".21"/>
<circle cx="171.4" cy="178.7" r=".49" fill="#000080"/>
<circle cx="171.4" cy="178.7" r=".49" fill="none" stroke="#000080" stroke-width=".21"/>
<path d="M193 176.1v2.6h-15.2" fill="none" stroke="#000080" stroke-width=".25"/>
<circle cx="177.7" cy="178.7" r=".49" fill="#000080"/>
<circle cx="177.7" cy="178.7" r=".49" fill="none" stroke="#000080" stroke-width=".21"/>
<path d="M51.8 155.8h8.9" fill="none" stroke="#000080" stroke-width=".25"/>
<circle cx="60.7" cy="155.8" r=".5" fill="#000080"/>
<circle cx="60.7" cy="155.8" r=".5" fill="none" stroke="#000080" stroke-width=".21"/>
<path d="M177.8 150.7v5.1" fill="none" stroke="#000080" stroke-width=".25"/>
<circle cx="177.7" cy="155.8" r=".74" fill="#000080"/>
<circle cx="177.7" cy="155.8" r=".74" fill="none" stroke="#000080" stroke-width=".21"/>
<path d="M187.9 150.7v5.1" fill="none" stroke="#000080" stroke-width=".25"/>
<circle cx="187.9" cy="155.8" r=".74" fill="#000080"/>
<circle cx="187.9" cy="155.8" r=".74" fill="none" stroke="#000080" stroke-width=".21"/>
<path d="M73.4 150.7v5.1" fill="none" stroke="#000080" stroke-width=".25"/>
<circle cx="73.4" cy="155.8" r=".48" fill="#000080"/>
<circle cx="73.4" cy="155.8" r=".48" fill="none" stroke="#000080" stroke-width=".21"/>
<path d="M86.2 150.7v5.1" fill="none" stroke="#000080" stroke-width=".25"/>
<circle cx="86.1" cy="155.8" r=".48" fill="#000080"/>
<circle cx="86.1" cy="155.8" r=".48" fill="none" stroke="#000080" stroke-width=".21"/>
<path d="M119.2 46.5v12.7h5.1" fill="none" stroke="#000080" stroke-width=".25"/>
<circle cx="124.3" cy="59.2" r=".49" fill="#000080"/>
<circle cx="124.3" cy="59.2" r=".49" fill="none" stroke="#000080" stroke-width=".21"/>
<path d="M152.3 166v2.5" fill="none" stroke="#000" stroke-width=".25"/>
<circle cx="152.3" cy="168.5" r=".49" fill="#000080"/>
<circle cx="152.3" cy="168.5" r=".49" fill="none" stroke="#000080" stroke-width=".21"/>
<path d="M152.3 158.4v2.5M151.3 160.9h2v5h-2z" fill="none" stroke="#000" stroke-width=".25"/>
<circle cx="152.3" cy="168.5" r=".49" fill="#000080"/>
<circle cx="152.3" cy="168.5" r=".49" fill="none" stroke="#000080" stroke-width=".21"/>
<path d="M69.1 79.5a.74 .74 0 0 0-.8-.7 .74 .74 0 0 0-.7 .7h-1.8v28M70.9 77.8v1.7h-1.8M70.9 75.2v1a.72 .72 0 0 1 .7 .8 .72 .72 0 0 1-.7 .7M70.9 71.9v1.8a.74 .74 0 0 1 .7 .7 .74 .74 0 0 1-.7 .7" fill="none" stroke="#000080" stroke-width=".25"/>
<circle cx="70.9" cy="71.9" r=".49" fill="#000080"/>
<circle cx="70.9" cy="71.9" r=".49" fill="none" stroke="#000080" stroke-width=".21"/>
<path d="M65.8 46.5v22.1a.74 .74 0 0 1 .7 .7 .74 .74 0 0 1-.7 .8M65.8 70.1v1a.74 .74 0 0 1 .7 .8 .74 .74 0 0 1-.7 .7M65.8 72.6v1.9" fill="none" stroke="#000080" stroke-width=".25"/>
<circle cx="65.8" cy="74.4" r=".49" fill="#000080"/>
<circle cx="65.8" cy="74.4" r=".49" fill="none" stroke="#000080" stroke-width=".21"/>
<path d="M25.2 26.2h106.7v12.6h-106.7z" fill="#ffffb0"/>
<path d="M25.1 26.2h106.8v12.6h-106.8z" fill="none" stroke="#800000" stroke-width=".21"/>
<g fill="none" stroke="#000" stroke-width=".25">
<path d="M27.6 18.5v7.6M30.2 38.9v7.6M32.8 38.9v7.6M35.3 38.9v7.6M37.8 38.9v7.6M40.4 38.9v7.6M42.9 38.9v7.6M45.5 38.9v7.6M48 38.9v7.6M50.5 38.9v7.6M53.1 38.9v7.6M55.7 38.9v7.6"/>
<path d="M58.2 38.9v7.6M60.7 38.9v7.6M63.3 38.9v7.6M65.8 38.9v7.6M68.4 38.9v7.6M70.9 38.9v7.6M73.4 38.9v7.6M76 38.9v7.6M78.5 38.9v7.6M81.1 38.9v7.6M83.6 38.9v7.6M86.2 38.9v7.6"/>
<path d="M88.7 38.9v7.6M91.3 38.9v7.6M93.8 38.9v7.6M96.3 38.9v7.6M98.9 38.9v7.6M101.4 38.9v7.6M104 38.9v7.6M106.5 38.9v7.6M109 38.9v7.6M111.6 38.9v7.6M114.2 38.9v7.6M116.7 38.9v7.6"/>
<path d="M119.2 38.9v7.6M121.8 38.9v7.6M124.3 38.9v7.6M126.9 38.9v7.6M129.4 38.9v7.6"/>
</g>
<circle cx="27.6" cy="18.5" r=".48" fill="#000080"/>
<circle cx="27.6" cy="18.5" r=".48" fill="none" stroke="#000080" stroke-width=".21"/>
<path d="M30.2 18.5v7.6" fill="none" stroke="#000" stroke-width=".25"/>
<circle cx="27.6" cy="18.5" r=".48" fill="#000080"/>
<circle cx="27.6" cy="18.5" r=".48" fill="none" stroke="#000080" stroke-width=".21"/>
<path d="M124.3 59.2h2.6" fill="none" stroke="#000080" stroke-width=".25"/>
<circle cx="124.3" cy="59.2" r=".49" fill="#000080"/>
<circle cx="124.3" cy="59.2" r=".49" fill="none" stroke="#000080" stroke-width=".21"/>
<path d="M124.3 46.5v12.7" fill="none" stroke="#000080" stroke-width=".25"/>
<circle cx="124.3" cy="59.2" r=".49" fill="#000080"/>
<circle cx="124.3" cy="59.2" r=".49" fill="none" stroke="#000080" stroke-width=".21"/>
<path d="M20 18.5v2.5M17.5 21h5.1M18.2 21.8h3.6M19 22.6h2M19.8 23.3h.5" fill="none" stroke="#800000" stroke-width=".25"/>
<path d="M20 18.5h10.2M37.8 46.5v12.7M221 99.9h-127.2v7.6" fill="none" stroke="#000080" stroke-width=".25"/>
<path d="M193 155.8v2.6M193 163.4v2.6" fill="none" stroke="#000" stroke-width=".25"/>
<circle cx="193" cy="155.8" r=".73" fill="#000080"/>
<circle cx="193" cy="155.8" r=".73" fill="none" stroke="#000080" stroke-width=".21"/>
<path d="M192 158.4h2v5h-2z" fill="none" stroke="#000" stroke-width=".25"/>
<circle cx="193" cy="155.8" r=".73" fill="#000080"/>
<circle cx="193" cy="155.8" r=".73" fill="none" stroke="#000080" stroke-width=".21"/>
<path d="M58.2 46.5v11.4" fill="none" stroke="#000080" stroke-width=".25"/>
<use href="#words"/>
</svg>
